VERSION 5.7 ;
  NOWIREEXTENSIONATPIN ON ;
  DIVIDERCHAR "/" ;
  BUSBITCHARS "[]" ;
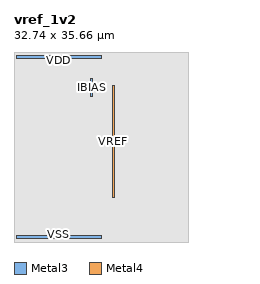
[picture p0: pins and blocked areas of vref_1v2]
MACRO vref_1v2
  CLASS BLOCK ;
  FOREIGN vref_1v2 ;
  ORIGIN 16.480 3.940 ;
  SIZE 32.740 BY 35.660 ;
  PIN IBIAS
    ANTENNAGATEAREA 32.000000 ;
    ANTENNADIFFAREA 1.200000 ;
    PORT
      LAYER Metal3 ;
        RECT -2.060 23.440 -1.780 26.780 ;
    END
  END IBIAS
  PIN VREF
    ANTENNAGATEAREA 74.134995 ;
    ANTENNADIFFAREA 3.888000 ;
    PORT
      LAYER Metal4 ;
        RECT 2.020 4.340 2.300 25.480 ;
    END
  END VREF
  PIN VSS
    USE GROUND ;
    PORT
      LAYER Metal3 ;
        RECT -16.060 -3.220 -0.020 -2.660 ;
    END
  END VSS
  PIN VDD
    USE POWER ;
    PORT
      LAYER Metal3 ;
        RECT -16.060 30.440 -0.020 31.000 ;
    END
  END VDD
  OBS
      LAYER Nwell ;
        RECT -13.265 0.000 13.265 27.680 ;
      LAYER Metal1 ;
        RECT -13.035 0.210 13.035 27.470 ;
      LAYER Metal2 ;
        RECT -13.035 0.210 13.630 27.910 ;
      LAYER Metal3 ;
        RECT -16.480 30.860 -16.060 31.000 ;
        RECT -16.480 30.580 -16.340 30.860 ;
        RECT -16.480 30.440 -16.060 30.580 ;
        RECT -16.480 30.140 -16.360 30.440 ;
        RECT 0.280 30.140 15.700 31.000 ;
        RECT -16.480 27.080 15.700 30.140 ;
        RECT -16.480 23.140 -2.360 27.080 ;
        RECT -1.480 23.140 15.700 27.080 ;
        RECT -16.480 -2.360 15.700 23.140 ;
        RECT -16.480 -2.660 -16.360 -2.360 ;
        RECT -16.480 -2.800 -16.060 -2.660 ;
        RECT -16.480 -3.080 -16.340 -2.800 ;
        RECT -16.480 -3.220 -16.060 -3.080 ;
        RECT 0.280 -3.220 15.700 -2.360 ;
      LAYER Metal4 ;
        RECT -16.450 25.780 15.670 30.970 ;
        RECT -16.450 4.040 1.720 25.780 ;
        RECT 2.600 4.040 15.670 25.780 ;
        RECT -16.450 -3.190 15.670 4.040 ;
      LAYER Metal5 ;
        RECT -16.450 -3.940 16.260 31.720 ;
  END
END vref_1v2
END LIBRARY

